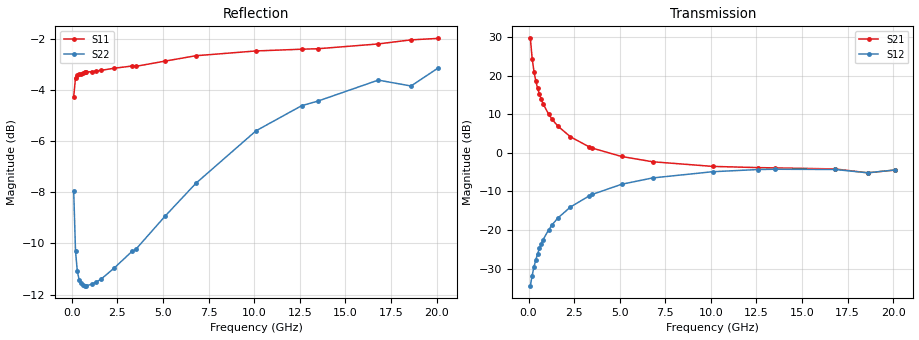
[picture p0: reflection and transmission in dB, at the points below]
!  Infineon Technologies AG
! BFR380L3 , PF131585-7, No.6, Th 09.10.01, soldered on pcb-board, measured with PP GSG850
!  Vce=1.0 V,  Ic=75.0 mA
! Common Emitter S-Parameters:  15. November 2001
#  GHz  S  MA  R  50
! f  S11  S21  S12  S22
! GHz  Mag  Ang  Mag  Ang  Mag  Ang  Mag  Ang
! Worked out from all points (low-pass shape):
!   201 points, 100 MHz to 20.1 GHz, reference 50 ohm
!   highest |S21| = 29.68 dB at 100 MHz (marker M1); lowest = -5.2 dB at 18.6 GHz (marker M2)
!   |S21| within 3 dB of the highest: start of sweep to 156.9 MHz
!   lowest |S11| = -4.3 dB at 100 MHz (marker M3), VSWR 4.15, Z = 13.3 - j15.6 ohm
!   |S11| at or under -10 dB: nowhere
!   |S22| runs from -11.7 to -3.1 dB; largest |S21 - S12| = 30
!   S11 on the Smith chart (normalised r, x): 100 MHz: 0.27, -0.31; 800 MHz: 0.19, +0.06; 3.3 GHz: 0.20, +0.40; 6.8 GHz: 0.27, +0.86; 12.6 GHz: 0.52, +1.60; 20.1 GHz: 1.01, +2.65
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0.1  0.612 -143.1  30.46 116.2  0.01903 52.4  0.4015 -96.7
0.2  0.6677 -162.9  16.59 101.2  0.02571 56.2  0.306 -129.4
0.3  0.6747 -171.0  11.29 94.9  0.03342 61.5  0.2787 -144.9
0.4  0.6783 -175.6  8.529 90.8  0.04129 65.2  0.2686 -153.8
0.5  0.6796 -179.2  6.852 87.6  0.04934 67.3  0.2645 -159.6
0.6  0.6825 177.9  5.73 85.0  0.05814 68.7  0.2623 -163.7
0.7  0.6847 175.5  4.928 82.5  0.06645 69.5  0.2615 -166.9
0.8  0.6853 173.2  4.324 80.3  0.07505 69.9  0.2614 -169.4
1.1  0.6864 167.5  3.182 74.4  0.1004 69.8  0.2632 -174.9
1.3  0.6881 164.0  2.711 70.8  0.1174 69.0  0.2653 -177.7
1.6  0.6904 159.0  2.233 65.6  0.1426 67.5  0.2692 179.0
2.3  0.6969 148.4  1.615 54.7  0.199 62.7  0.2826 172.3
3.3  0.7041 134.5  1.206 41.1  0.275 54.8  0.3052 163.7
3.5  0.703 131.9  1.153 38.7  0.2898 53.2  0.3078 162.4
5.1  0.7197 113.0  0.8984 22.1  0.3919 40.0  0.3573 148.9
6.8  0.7375 96.1  0.7677 9.6  0.4736 27.2  0.4148 134.0
10.1  0.7536 72.4  0.6682 -7.3  0.5702 5.4  0.5257 109.8
12.6  0.7595 60.2  0.6445 -17.5  0.6088 -9.2  0.5887 92.4
13.5  0.7612 56.4  0.639 -21.4  0.6139 -14.1  0.6012 87.1
16.8  0.7778 45.5  0.6197 -32.7  0.6098 -28.6  0.6607 69.6
18.6  0.7922 42.7  0.5518 -38.5  0.5521 -35.2  0.6434 65.6
20.1  0.7976 37.0  0.5998 -43.8  0.6009 -41.1  0.6984 55.5
